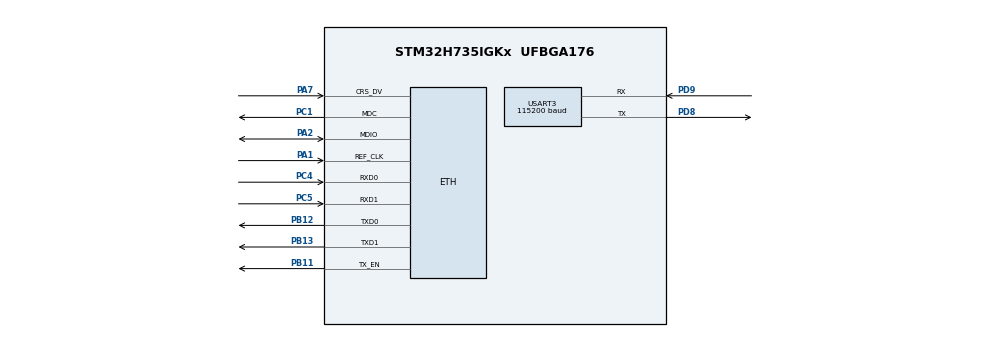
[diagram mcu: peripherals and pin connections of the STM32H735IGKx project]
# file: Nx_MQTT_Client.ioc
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CORTEX_M7.AccessPermission-Cortex_Memory_Protection_Unit_Region0_Settings=MPU_REGION_FULL_ACCESS
CORTEX_M7.AccessPermission-Cortex_Memory_Protection_Unit_Region1_Settings=MPU_REGION_FULL_ACCESS
CORTEX_M7.BaseAddress-Cortex_Memory_Protection_Unit_Region0_Settings=0x24030000
CORTEX_M7.BaseAddress-Cortex_Memory_Protection_Unit_Region1_Settings=0x24030000
CORTEX_M7.CPU_DCache=Enabled
CORTEX_M7.CPU_ICache=Enabled
CORTEX_M7.Enable-Cortex_Memory_Protection_Unit_Region0_Settings=MPU_REGION_ENABLE
CORTEX_M7.Enable-Cortex_Memory_Protection_Unit_Region1_Settings=MPU_REGION_ENABLE
CORTEX_M7.IsBufferable-Cortex_Memory_Protection_Unit_Region1_Settings=MPU_ACCESS_BUFFERABLE
CORTEX_M7.IsCacheable-Cortex_Memory_Protection_Unit_Region0_Settings=MPU_ACCESS_CACHEABLE
CORTEX_M7.MPU_Control=MPU_PRIVILEGED_DEFAULT
CORTEX_M7.Size-Cortex_Memory_Protection_Unit_Region0_Settings=MPU_REGION_SIZE_128KB
CORTEX_M7.Size-Cortex_Memory_Protection_Unit_Region1_Settings=MPU_REGION_SIZE_256B
CORTEX_M7.TypeExtField-Cortex_Memory_Protection_Unit_Region0_Settings=MPU_TEX_LEVEL0
CORTEX_M7.TypeExtField-Cortex_Memory_Protection_Unit_Region1_Settings=MPU_TEX_LEVEL1
ETH.MACAddr=00\:80\:E1\:01\:00\:00
ETH.MediaInterface=HAL_ETH_RMII_MODE
ETH.RxBuffLen=1536
ETH.RxDescAddress=0x24030000
ETH.TxDescAddress=0x24030060
Mcu.Family=STM32H7
Mcu.Name=STM32H735IGKx
Mcu.Package=UFBGA176
NVIC.ETH_IRQn=true\:7\:0\:true\:false\:true\:false\:true\:true
NVIC.PriorityGroup=NVIC_PRIORITYGROUP_4
NVIC.TIM6_DAC_IRQn=true\:0\:0\:false\:false\:true\:false\:false\:true
NVIC.TimeBase=TIM6_DAC_IRQn
NVIC.TimeBaseIP=TIM6
PA1.Mode=RMII
PA1.Signal=ETH_REF_CLK
PA2.Mode=RMII
PA2.Signal=ETH_MDIO
PA7.Mode=RMII
PA7.Signal=ETH_CRS_DV
PB11.Mode=RMII
PB11.Signal=ETH_TX_EN
PB12.Mode=RMII
PB12.Signal=ETH_TXD0
PB13.Mode=RMII
PB13.Signal=ETH_TXD1
PC1.Mode=RMII
PC1.Signal=ETH_MDC
PC4.Mode=RMII
PC4.Signal=ETH_RXD0
PC5.Mode=RMII
PC5.Signal=ETH_RXD1
PD8.Mode=Asynchronous
PD8.Signal=USART3_TX
PD9.Mode=Asynchronous
PD9.Signal=USART3_RX
PH0-OSC_IN.Mode=HSE-External-Oscillator
PH0-OSC_IN.Signal=RCC_OSC_IN
PH1-OSC_OUT.Mode=HSE-External-Oscillator
PH1-OSC_OUT.Signal=RCC_OSC_OUT
ProjectManager.HeapSize=0x1000
ProjectManager.StackSize=0x1000
ProjectManager.TargetToolchain=EWARM V8.32
RCC.ADCFreq_Value=50390625
RCC.APB1Freq_Value=130000000
RCC.APB2Freq_Value=130000000
RCC.APB3Freq_Value=130000000
RCC.APB4Freq_Value=130000000
RCC.CortexFreq_Value=520000000
RCC.D1PPRE=RCC_APB3_DIV2
RCC.D2PPRE1=RCC_APB1_DIV2
RCC.D2PPRE2=RCC_APB2_DIV2
RCC.D3PPRE=RCC_APB4_DIV2
RCC.DIVM1=5
RCC.DIVN1=104
RCC.DIVP1=1
RCC.HCLKFreq_Value=260000000
RCC.HPRE=RCC_HCLK_DIV2
RCC.HSE_VALUE=25000000
RCC.PLL2FRACN=0
RCC.PLL3FRACN=0
RCC.PLLFRACN=0
RCC.PLLSourceVirtual=RCC_PLLSOURCE_HSE
RCC.SYSCLKFreq_VALUE=520000000
RCC.SYSCLKSource=RCC_SYSCLKSOURCE_PLLCLK
RCC.SupplySource=PWR_DIRECT_SMPS_SUPPLY
RCC.USBFreq_Value=260000000
STMicroelectronics.X-CUBE-AZRTOS-H7.2.0.0.AZRTOSIiApplicationsCcDeviceJjApplication=azureIirtosIiapp
STMicroelectronics.X-CUBE-AZRTOS-H7.2.0.0.AZRTOSIiApplicationsCcDeviceJjHWIiProfile=STM32H735GIiDISCO
STMicroelectronics.X-CUBE-AZRTOS-H7.2.0.0.AZUREIiRTOSIiApplicationsCcDeviceJjApplication=azureIirtosIiapp
STMicroelectronics.X-CUBE-AZRTOS-H7.2.0.0.AZUREIiRTOSIiApplicationsCcDeviceJjHWIiProfile=STM32H735GIiDK
STMicroelectronics.X-CUBE-AZRTOS-H7.2.0.0.InterfacesCcNetworkJjEthernetOoInterface=true
STMicroelectronics.X-CUBE-AZRTOS-H7.2.0.0.InterfacesCcNetworkJjEthernetOoPhyOoInterface=LAN8742IiPhyIiInterface
STMicroelectronics.X-CUBE-AZRTOS-H7.2.0.0.NXD_MQTT_REQUIRE_TLS=true
STMicroelectronics.X-CUBE-AZRTOS-H7.2.0.0.NX_APP_MEM_POOL_SIZE=1024 * 80
STMicroelectronics.X-CUBE-AZRTOS-H7.2.0.0.NX_DNS_MAX_RETRIES=10
STMicroelectronics.X-CUBE-AZRTOS-H7.2.0.0.NX_ENABLE_INTERFACE_CAPABILITY=true
STMicroelectronics.X-CUBE-AZRTOS-H7.2.0.0.NX_SECURE_ENABLE=true
STMicroelectronics.X-CUBE-AZRTOS-H7.2.0.0.NX_SECURE_ENABLE_AEAD_CIPHER=false
STMicroelectronics.X-CUBE-AZRTOS-H7.2.0.0.NX_SECURE_TLS_ENABLE_TLS_1_1=false
STMicroelectronics.X-CUBE-AZRTOS-H7.2.0.0.NX_SECURE_TLS_ENABLE_TLS_1_3=false
STMicroelectronics.X-CUBE-AZRTOS-H7.2.0.0.NX_SECURE_TLS_TLS_1_2_ENABLED=true
STMicroelectronics.X-CUBE-AZRTOS-H7.2.0.0.NX_SECURE_TLS_TLS_1_3_ENABLED=false
STMicroelectronics.X-CUBE-AZRTOS-H7.2.0.0.NetXDuoCcNetworkJjNetXDuoJjAddonsOoDHCPOoClient=true
STMicroelectronics.X-CUBE-AZRTOS-H7.2.0.0.NetXDuoCcNetworkJjNetXDuoJjAddonsOoDNS=true
STMicroelectronics.X-CUBE-AZRTOS-H7.2.0.0.NetXDuoCcNetworkJjNetXDuoJjAddonsOoMQTT=true
STMicroelectronics.X-CUBE-AZRTOS-H7.2.0.0.NetXDuoCcNetworkJjNetXDuoJjCrypto=true
STMicroelectronics.X-CUBE-AZRTOS-H7.2.0.0.NetXDuoCcNetworkJjNetXDuoJjCryptoOoCore=true
STMicroelectronics.X-CUBE-AZRTOS-H7.2.0.0.NetXDuoCcNetworkJjNetXDuoJjCryptoOoSHA256=SWIiImplementation
STMicroelectronics.X-CUBE-AZRTOS-H7.2.0.0.NetXDuoCcNetworkJjNetXDuoJjNXOoCore=true
STMicroelectronics.X-CUBE-AZRTOS-H7.2.0.0.NetXDuoCcNetworkJjNetXDuoJjTLS=true
STMicroelectronics.X-CUBE-AZRTOS-H7.2.0.0.NetXDuoCcNetworkJjNetXDuoJjTLSOoCore=true
STMicroelectronics.X-CUBE-AZRTOS-H7.2.0.0.STM32CubeIiBSPIiComponentsCcBoardOoPartJjETHPhyJjLAN8742=true
STMicroelectronics.X-CUBE-AZRTOS-H7.2.0.0.ThreadXCcRTOSJjThreadXJjCore=true
STMicroelectronics.X-CUBE-AZRTOS-H7.2.0.0.ThreadXCcRTOSJjThreadXJjPerformanceInfo=true
STMicroelectronics.X-CUBE-AZRTOS-H7.2.0.0_IsAnAzureRtosMw=true
USART3.BaudRate=115200
USART3.Parity=PARITY_NONE
USART3.VirtualMode-Asynchronous=VM_ASYNC
VP_RNG_VS_RNG.Mode=RNG_Activate
VP_STMicroelectronics.X-CUBE-AZRTOS-H7_VS_BoardOoPartJjSTM32CubeIiBSPIiComponents_1.1.0_2.0.0.Mode=BoardOoPartJjSTM32CubeIiBSPIiComponents
VP_STMicroelectronics.X-CUBE-AZRTOS-H7_VS_NetworkJjInterfaces_2.0.0_2.0.0.Mode=NetworkJjInterfaces
VP_STMicroelectronics.X-CUBE-AZRTOS-H7_VS_NetworkJjNetXDuo_6.1.7_2.0.0.Mode=NetworkJjNetXDuo
VP_STMicroelectronics.X-CUBE-AZRTOS-H7_VS_RTOSJjThreadX_6.1.7_2.0.0.Mode=RTOSJjThreadX
VP_SYS_VS_tim6.Mode=TIM6
board=STM32H735G-DK

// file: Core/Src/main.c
/* USER CODE BEGIN Header */
/**
  ******************************************************************************
  * @file           : main.c
  * @brief          : Main program body
  ******************************************************************************
  * @attention
  *
  * Copyright (c) 2020-2021 STMicroelectronics.
  * All rights reserved.
  *
  * This software is licensed under terms that can be found in the LICENSE file
  * in the root directory of this software component.
  * If no LICENSE file comes with this software, it is provided AS-IS.
  *
  ******************************************************************************
  */
/* USER CODE END Header */
#include "main.h"
#include "string.h"
#include "app_threadx.h"

/* USER CODE BEGIN Includes */
#include "stdio.h"
#include   "stm32h735g_discovery.h"
/* USER CODE END Includes */

/* USER CODE BEGIN PD */
#if defined ( __GNUC__) && !defined(__clang__)
#define PUTCHAR_PROTOTYPE int __io_putchar(int ch)
#else
#define PUTCHAR_PROTOTYPE int fputc(int ch, FILE *f)
#endif
/* USER CODE END PD */

#if defined ( __ICCARM__ ) /*!< IAR Compiler */

#pragma location=0x24030000
ETH_DMADescTypeDef  DMARxDscrTab[ETH_RX_DESC_CNT]; /* Ethernet Rx DMA Descriptors */
#pragma location=0x24030060
ETH_DMADescTypeDef  DMATxDscrTab[ETH_TX_DESC_CNT]; /* Ethernet Tx DMA Descriptors */

#elif defined ( __CC_ARM )  /* MDK ARM Compiler */

__attribute__((at(0x24030000))) ETH_DMADescTypeDef  DMARxDscrTab[ETH_RX_DESC_CNT]; /* Ethernet Rx DMA Descriptors */
__attribute__((at(0x24030060))) ETH_DMADescTypeDef  DMATxDscrTab[ETH_TX_DESC_CNT]; /* Ethernet Tx DMA Descriptors */

#elif defined ( __GNUC__ ) /* GNU Compiler */

ETH_DMADescTypeDef DMARxDscrTab[ETH_RX_DESC_CNT] __attribute__((section(".RxDecripSection"))); /* Ethernet Rx DMA Descriptors */
ETH_DMADescTypeDef DMATxDscrTab[ETH_TX_DESC_CNT] __attribute__((section(".TxDecripSection")));   /* Ethernet Tx DMA Descriptors */

#endif

ETH_TxPacketConfig TxConfig;

ETH_HandleTypeDef heth;

RNG_HandleTypeDef hrng;

UART_HandleTypeDef huart3;

void SystemClock_Config(void);
static void MPU_Config(void);
static void MX_GPIO_Init(void);
static void MX_USART3_UART_Init(void);
static void MX_RNG_Init(void);

/* USER CODE BEGIN 0 */
void Success_Handler(void)
{
   BSP_LED_Off(LED_RED);
   while(1)
   {
     BSP_LED_Toggle(LED_GREEN);
     tx_thread_sleep(50);
   }
}
/* USER CODE END 0 */

int main(void)
{

  /* MPU Configuration--------------------------------------------------------*/
  MPU_Config();

  /* Enable I-Cache---------------------------------------------------------*/
  SCB_EnableICache();

  /* Enable D-Cache---------------------------------------------------------*/
  SCB_EnableDCache();

  /* MCU Configuration--------------------------------------------------------*/

  /* Reset of all peripherals, Initializes the Flash interface and the Systick. */
  HAL_Init();

  /* Configure the system clock */
  SystemClock_Config();

  /* USER CODE BEGIN SysInit */
  BSP_LED_Init(LED_GREEN);
  BSP_LED_Init(LED_RED);
  /* USER CODE END SysInit */

  /* Initialize all configured peripherals */
  MX_GPIO_Init();
  MX_USART3_UART_Init();
  MX_RNG_Init();

  MX_ThreadX_Init();
  /* Infinite loop */
  while (1)
  {

  }
}

void SystemClock_Config(void)
{
   RCC_OscInitTypeDef RCC_OscInitStruct = {0};
   RCC_ClkInitTypeDef RCC_ClkInitStruct = {0};

   // Supply configuration update enable
   HAL_PWREx_ConfigSupply(PWR_LDO_SUPPLY);

   // Configure the main internal regulator output voltage
   __HAL_PWR_VOLTAGESCALING_CONFIG(PWR_REGULATOR_VOLTAGE_SCALE1);

   while(!__HAL_PWR_GET_FLAG(PWR_FLAG_VOSRDY)) {}
   /** Initializes the RCC Oscillators according to the specified parameters
   * in the RCC_OscInitTypeDef structure.
   */
   RCC_OscInitStruct.OscillatorType = RCC_OSCILLATORTYPE_HSI48|RCC_OSCILLATORTYPE_HSE;
   RCC_OscInitStruct.HSEState = RCC_HSE_ON;
   RCC_OscInitStruct.HSI48State = RCC_HSI48_ON;
   RCC_OscInitStruct.PLL.PLLState = RCC_PLL_ON;
   RCC_OscInitStruct.PLL.PLLSource = RCC_PLLSOURCE_HSE;
   RCC_OscInitStruct.PLL.PLLM = 1;
   RCC_OscInitStruct.PLL.PLLN = 100;
   RCC_OscInitStruct.PLL.PLLP = 2;
   RCC_OscInitStruct.PLL.PLLQ = 2;
   RCC_OscInitStruct.PLL.PLLR = 2;
   RCC_OscInitStruct.PLL.PLLRGE = RCC_PLL1VCIRANGE_3;
   RCC_OscInitStruct.PLL.PLLVCOSEL = RCC_PLL1VCOWIDE;
   RCC_OscInitStruct.PLL.PLLFRACN = 0;
   if (HAL_RCC_OscConfig(&RCC_OscInitStruct) != HAL_OK)
   {
      Error_Handler();
   }
   /** Initializes the CPU, AHB and APB buses clocks
   */
   RCC_ClkInitStruct.ClockType = RCC_CLOCKTYPE_HCLK|RCC_CLOCKTYPE_SYSCLK
                              |RCC_CLOCKTYPE_PCLK1|RCC_CLOCKTYPE_PCLK2
                              |RCC_CLOCKTYPE_D3PCLK1|RCC_CLOCKTYPE_D1PCLK1;
   RCC_ClkInitStruct.SYSCLKSource = RCC_SYSCLKSOURCE_PLLCLK;
   RCC_ClkInitStruct.SYSCLKDivider = RCC_SYSCLK_DIV1;
   RCC_ClkInitStruct.AHBCLKDivider = RCC_HCLK_DIV2;
   RCC_ClkInitStruct.APB3CLKDivider = RCC_APB3_DIV2;
   RCC_ClkInitStruct.APB1CLKDivider = RCC_APB1_DIV2;
   RCC_ClkInitStruct.APB2CLKDivider = RCC_APB2_DIV2;
   RCC_ClkInitStruct.APB4CLKDivider = RCC_APB4_DIV2;

   if (HAL_RCC_ClockConfig(&RCC_ClkInitStruct, FLASH_LATENCY_3) != HAL_OK)
   {
      Error_Handler();
   }
}

void MX_ETH_Init(void)
{

   static uint8_t MACAddr[6];

  heth.Instance = ETH;
  MACAddr[0] = 0x00;
  MACAddr[1] = 0x80;
  MACAddr[2] = 0xE1;
  MACAddr[3] = 0x01;
  MACAddr[4] = 0x00;
  MACAddr[5] = 0x00;
  heth.Init.MACAddr = &MACAddr[0];
  heth.Init.MediaInterface = HAL_ETH_RMII_MODE;
  heth.Init.TxDesc = DMATxDscrTab;
  heth.Init.RxDesc = DMARxDscrTab;
  heth.Init.RxBuffLen = 1536;

  if (HAL_ETH_Init(&heth) != HAL_OK)
  {
    Error_Handler();
  }

  memset(&TxConfig, 0 , sizeof(ETH_TxPacketConfig));
  TxConfig.Attributes = ETH_TX_PACKETS_FEATURES_CSUM | ETH_TX_PACKETS_FEATURES_CRCPAD;
  TxConfig.ChecksumCtrl = ETH_CHECKSUM_IPHDR_PAYLOAD_INSERT_PHDR_CALC;
  TxConfig.CRCPadCtrl = ETH_CRC_PAD_INSERT;

}

static void MX_RNG_Init(void)
{

  hrng.Instance = RNG;
  hrng.Init.ClockErrorDetection = RNG_CED_ENABLE;
  if (HAL_RNG_Init(&hrng) != HAL_OK)
  {
    Error_Handler();
  }

}

static void MX_USART3_UART_Init(void)
{

  huart3.Instance = USART3;
  huart3.Init.BaudRate = 115200;
  huart3.Init.WordLength = UART_WORDLENGTH_8B;
  huart3.Init.StopBits = UART_STOPBITS_1;
  huart3.Init.Parity = UART_PARITY_NONE;
  huart3.Init.Mode = UART_MODE_TX_RX;
  huart3.Init.HwFlowCtl = UART_HWCONTROL_NONE;
  huart3.Init.OverSampling = UART_OVERSAMPLING_16;
  huart3.Init.OneBitSampling = UART_ONE_BIT_SAMPLE_DISABLE;
  huart3.Init.ClockPrescaler = UART_PRESCALER_DIV1;
  huart3.AdvancedInit.AdvFeatureInit = UART_ADVFEATURE_NO_INIT;
  if (HAL_UART_Init(&huart3) != HAL_OK)
  {
    Error_Handler();
  }
  if (HAL_UARTEx_SetTxFifoThreshold(&huart3, UART_TXFIFO_THRESHOLD_1_8) != HAL_OK)
  {
    Error_Handler();
  }
  if (HAL_UARTEx_SetRxFifoThreshold(&huart3, UART_RXFIFO_THRESHOLD_1_8) != HAL_OK)
  {
    Error_Handler();
  }
  if (HAL_UARTEx_DisableFifoMode(&huart3) != HAL_OK)
  {
    Error_Handler();
  }

}

static void MX_GPIO_Init(void)
{

  /* GPIO Ports Clock Enable */
  __HAL_RCC_GPIOH_CLK_ENABLE();
  __HAL_RCC_GPIOD_CLK_ENABLE();
  __HAL_RCC_GPIOC_CLK_ENABLE();
  __HAL_RCC_GPIOB_CLK_ENABLE();
  __HAL_RCC_GPIOA_CLK_ENABLE();

}

/* USER CODE BEGIN 4 */
  /**
  * @brief  Retargets the C library printf function to the USART.
  * @param  None
  * @retval None
  */

PUTCHAR_PROTOTYPE
{
  HAL_UART_Transmit(&huart3, (uint8_t *)&ch, 1, 0xFFFF);
  return ch;
}
/* USER CODE END 4 */

/* MPU Configuration */

void MPU_Config(void)
{
  MPU_Region_InitTypeDef MPU_InitStruct = {0};

  /* Disables the MPU */
  HAL_MPU_Disable();
  /** Initializes and configures the Region and the memory to be protected
  */
  MPU_InitStruct.Enable = MPU_REGION_ENABLE;
  MPU_InitStruct.Number = MPU_REGION_NUMBER0;
  MPU_InitStruct.BaseAddress = 0x24030000;
  MPU_InitStruct.Size = MPU_REGION_SIZE_128KB;
  MPU_InitStruct.SubRegionDisable = 0x0;
  MPU_InitStruct.TypeExtField = MPU_TEX_LEVEL0;
  MPU_InitStruct.AccessPermission = MPU_REGION_FULL_ACCESS;
  MPU_InitStruct.DisableExec = MPU_INSTRUCTION_ACCESS_ENABLE;
  MPU_InitStruct.IsShareable = MPU_ACCESS_NOT_SHAREABLE;
  MPU_InitStruct.IsCacheable = MPU_ACCESS_CACHEABLE;
  MPU_InitStruct.IsBufferable = MPU_ACCESS_NOT_BUFFERABLE;

  HAL_MPU_ConfigRegion(&MPU_InitStruct);
  /** Initializes and configures the Region and the memory to be protected
  */
  MPU_InitStruct.Number = MPU_REGION_NUMBER1;
  MPU_InitStruct.Size = MPU_REGION_SIZE_256B;
  MPU_InitStruct.TypeExtField = MPU_TEX_LEVEL1;
  MPU_InitStruct.IsCacheable = MPU_ACCESS_NOT_CACHEABLE;
  MPU_InitStruct.IsBufferable = MPU_ACCESS_BUFFERABLE;

  HAL_MPU_ConfigRegion(&MPU_InitStruct);
  /* Enables the MPU */
  HAL_MPU_Enable(MPU_PRIVILEGED_DEFAULT);

}

void HAL_TIM_PeriodElapsedCallback(TIM_HandleTypeDef *htim)
{
  if (htim->Instance == TIM6) {
    HAL_IncTick();
  }
}

void Error_Handler(void)
{
  /* USER CODE BEGIN Error_Handler_Debug */
  /* User can add his own implementation to report the HAL error return state */
   BSP_LED_Off(LED_GREEN);
   while(1)
   {
     BSP_LED_Toggle(LED_RED);
     tx_thread_sleep(20);
   }
  /* USER CODE END Error_Handler_Debug */
}
